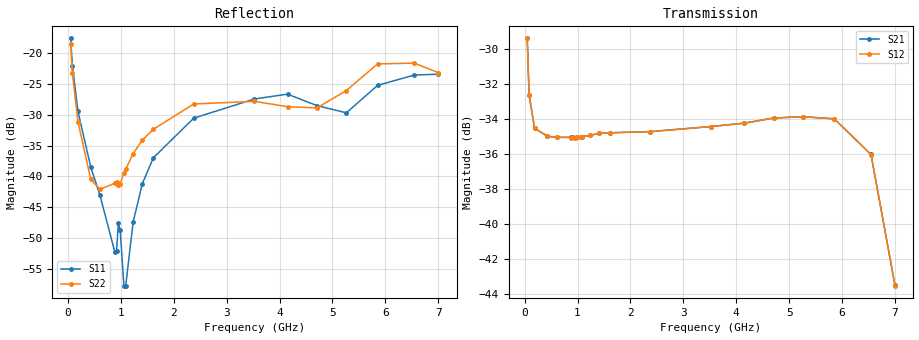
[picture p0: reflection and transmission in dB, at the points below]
! Integrated Device Technology
! Corporate Headquarters
! 6024 Silver Creek Valley Road
! San Jose, CA 95138  USA
! Phone:  1-408-284-8200
! Toll Free:  1-800-223-1366
! Webpage:  http://www.idt.com/
! Timing and RF Division
! 515 Groton Road, Suite 102
! Westford, MA 01886-6024
! Device:  F2258
! Description: Voltage Variable RF Attenuator
! Frequency:  50.0 -  6000.00 MHz
! Package:  3x3 mm Thin QFN Plastic Package: 16 pin
! Ports:  2 RF, 2 DC
!  Pin  1  = NC
!  Pin  2  = NC
!  Pin  3  = RF2  = Port 2
!  Pin  4  = GND
!  Pin  5  = Vdd
!  Pin  6  = NC
!  Pin  7  = VCTRL
!  Pin  8  = NC
!  Pin  9  = GND
!  Pin 10  = RF1  = Port 1
!  Pin 11  = NC
!  Pin 12  = NC
!  Pin 13  = NC
!  Pin 14  = NC
!  Pin 15  = NC
!  Pin 16  = NC
! Vcntrl:  2.020 Volts
! Vdd:  +3.300 Volts
! Current:  1.156 mA
! Data:  The device was measured on a the F2258 evaluation board which has
!  individual transmission lines to the RF pins.  Data was collected
!  using a calibrated network analyzer.  The evaluation board was
!  de-embedded using a TRL calibration technique.
!  The reference plane is the edge of the package pin.
! Misc:  SN 10
!  Action Tracker AT0285
! Date Measured:  2014-12-10
! Date:  2016-01-13  MJV
! Note:
!  Integrated Device Technology supplies this data as a sample of measured
!  data at the package pin for this product.  Your particular data for this
!  product may vary.
!  Data was taken at 25 degrees C.
!  Integrated Device Technology reserves the right to change this data at anytime.
!Freq_(GHz)  S11M_(dB)  S11P_(deg)  S21M_(dB)  S21P_(deg)  S12M_(dB)  S12P_(deg)  S22M_(dB)  S22P_(deg)
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# GHz S dB R 50
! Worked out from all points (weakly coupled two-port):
!   201 points, 50 MHz to 7 GHz, reference 50 ohm
!   highest |S21| = -29.37 dB at 50 MHz (marker M1); lowest = -43.5 dB at 7 GHz (marker M2)
!   lowest |S11| = -57.8 dB at 1.058 GHz (marker M3), VSWR 1.00, Z = 49.9 + j0.0552 ohm
!   |S11| at or under -10 dB: start of sweep to end of sweep
!   |S22| runs from -42.1 to -18.4 dB; largest |S21 - S12| = 8.6e-05
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0.05  -17.55 -110.9  -29.37 -66.9  -29.37 -66.9  -18.40 -108.5
0.08475  -21.98 -107.4  -32.61 -47.4  -32.60 -47.4  -23.25 -100.2
0.189  -29.42 -109.3  -34.52 -24.0  -34.52 -24.1  -31.09 -88.3
0.43225  -38.51 -119.5  -34.98 -12.3  -34.98 -12.3  -40.50 -47.4
0.606  -43.09 -125.7  -35.04 -10.0  -35.04 -10.0  -42.10 -9.3
0.884  -52.22 166.0  -35.04 -8.6  -35.05 -8.6  -41.12 23.2
0.91875  -52.13 150.0  -35.04 -8.6  -35.04 -8.6  -40.87 25.0
0.9535  -47.64 -162.5  -35.05 -8.5  -35.05 -8.5  -41.46 47.1
0.98825  -48.78 -173.7  -35.04 -8.4  -35.03 -8.4  -41.31 43.6
1.05775  -57.77 154.7  -35.02 -8.3  -35.02 -8.3  -39.37 39.5
1.0925  -57.75 117.9  -35.00 -8.2  -35.00 -8.2  -38.83 38.7
1.2315  -47.46 46.3  -34.93 -8.3  -34.93 -8.3  -36.31 32.4
1.40525  -41.20 33.2  -34.81 -9.0  -34.81 -9.0  -34.12 31.3
1.61375  -36.98 32.5  -34.78 -10.1  -34.78 -10.1  -32.34 26.2
2.37825  -30.52 48.1  -34.71 -13.9  -34.72 -13.9  -28.22 27.0
3.525  -27.41 91.6  -34.42 -20.6  -34.42 -20.6  -27.79 54.1
4.1505  -26.62 104.9  -34.23 -25.1  -34.23 -25.2  -28.66 63.9
4.7065  -28.49 95.6  -33.93 -29.9  -33.94 -29.9  -28.86 45.6
5.2625  -29.66 54.3  -33.86 -36.0  -33.86 -36.0  -26.04 9.1
5.85325  -25.19 29.8  -33.98 -46.4  -33.98 -46.5  -21.70 -9.9
6.54825  -23.51 45.0  -36.02 -66.6  -36.04 -66.7  -21.58 -43.7
7  -23.38 84.5  -43.50 -62.4  -43.54 -61.9  -23.12 -128.1
